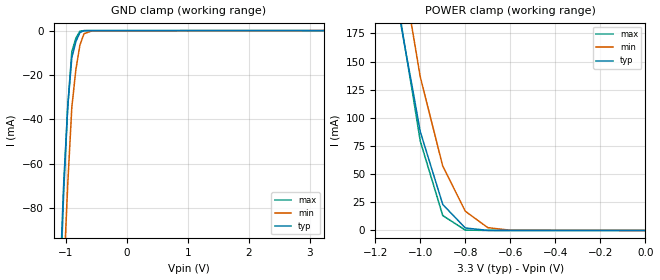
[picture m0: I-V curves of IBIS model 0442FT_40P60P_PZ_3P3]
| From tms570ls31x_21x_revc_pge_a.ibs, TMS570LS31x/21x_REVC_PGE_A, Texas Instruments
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|   Model Cell 0442FT_40P60P_PZ_3P3
|IQ0442FT_40P60P_PZ_3P3
[Model]   0442FT_40P60P_PZ_3P3
Model_type   Input
Polarity   Non-Inverting
Vinl =  1.55
Vinh =  1.75
C_comp   1.2p   1.2p   1.2p
[Model Spec]
Vinl   1.55   1.42   1.68
Vinh   1.75   1.55   1.85
[Temperature Range]   25   155   -40
[Voltage Range]   3.3   2.97   3.63
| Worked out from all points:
|   GND clamp passes 1 mA (typ) near -0.77 V on its own axis
|   POWER clamp passes 1 mA (typ) near -0.74 V on its own axis
[POWER_clamp]
|   voltage   I(typ)   I(min)   I(max)
-3.3V     3.541A     4.385A     3.783A
-1.1V     198.7mA    255.1mA    203.4mA
-1.067V   161.8mA    215.6mA    162.1mA
-1.033V   124.9mA    176.1mA    120.8mA
-1V       87.93mA    136.6mA    79.54mA
-900mV    23.11mA    57.15mA    13.26mA
-800mV    2.235mA    17.1mA     350.6uA
-700mV    70.13uA    2.515mA    5.198uA
-600mV    2.318uA    221.3uA    475.8nA
0V        280.4pA    424.1pA    308.7pA
[GND_clamp]
|   voltage   I(typ)   I(min)   I(max)
-3.3V     -2.707A    -2.59A     -3.853A
-1.1V     -116mA     -158.3mA   -124.9mA
-1.033V   -68.83mA   -110.6mA   -72.79mA
-966.7mV  -34.24mA   -69.38mA   -34.32mA
-900mV    -12.23mA   -34.62mA   -9.549mA
-833.3mV  -4.922mA   -17.55mA   -3.434mA
-766.7mV  -866.2uA   -6.476mA   -254.5uA
-700mV    -56.97uA   -1.408mA   -9.482uA
-566.7mV  -2.104uA   -110.8uA   -997.2nA
3.233V    270.2pA    105.1nA    247.6pA
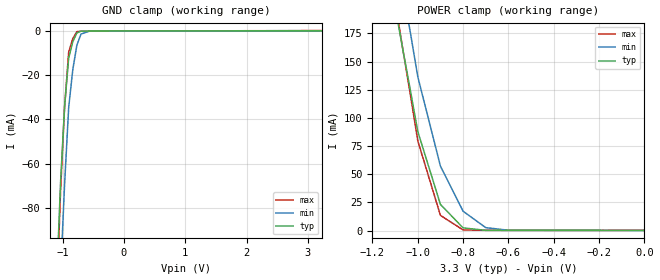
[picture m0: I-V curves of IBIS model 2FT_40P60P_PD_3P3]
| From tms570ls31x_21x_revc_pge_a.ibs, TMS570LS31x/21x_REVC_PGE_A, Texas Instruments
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|   Model Cell 2FT_40P60P_PD_3P3
|IQ0442FT_40P60P_PD_3P3
[Model]   2FT_40P60P_PD_3P3
Model_type   Input
Polarity   Non-Inverting
Vinl =  1.55
Vinh =  1.75
C_comp   1.2p   1.2p   1.2p
[Model Spec]
Vinl   1.55   1.42   1.68
Vinh   1.75   1.55   1.85
[Temperature Range]   25   155   -40
[Voltage Range]   3.3   2.97   3.63
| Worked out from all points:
|   GND clamp passes 1 mA (typ) near -0.77 V on its own axis
|   POWER clamp passes 1 mA (typ) near -0.74 V on its own axis
[POWER_clamp]
|   voltage   I(typ)   I(min)   I(max)
-3.3V     3.541A     4.385A     3.783A
-1.1V     198.8mA    255.1mA    203.5mA
-1.067V   161.8mA    215.6mA    162.2mA
-1.033V   124.9mA    176.1mA    120.9mA
-1V       87.98mA    136.6mA    79.67mA
-900mV    23.19mA    57.17mA    13.42mA
-800mV    2.329mA    17.13mA    516.8uA
-700mV    165.6uA    2.555mA    172.4uA
-600mV    98.49uA    264.7uA    168.8uA
0V        96.5uA     44.2uA     168.6uA
[GND_clamp]
|   voltage   I(typ)   I(min)   I(max)
-3.3V     -2.707A    -2.59A     -3.853A
-1.1V     -116mA     -158.3mA   -124.9mA
-1.033V   -68.85mA   -110.6mA   -72.8mA
-966.7mV  -34.25mA   -69.39mA   -34.34mA
-900mV    -12.25mA   -34.63mA   -9.575mA
-833.3mV  -4.958mA   -17.56mA   -3.496mA
-766.7mV  -914.6uA   -6.492mA   -337.7uA
-700mV    -116.1uA   -1.429mA   -100.1uA
-566.7mV  -52.65uA   -136.8uA   -76.88uA
3.233V    96.49uA    44.32uA    168.5uA
